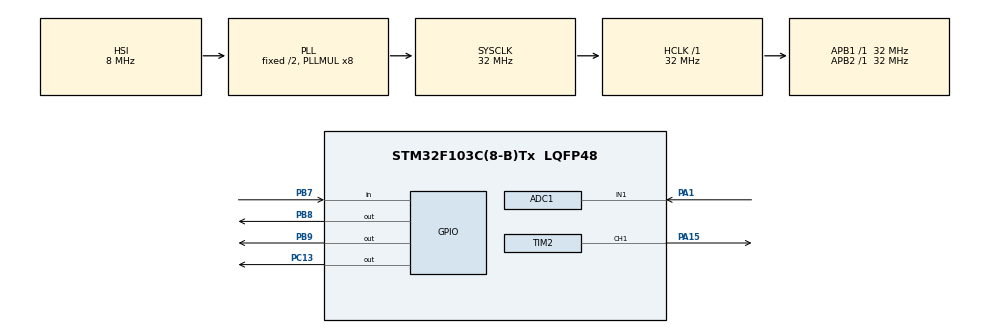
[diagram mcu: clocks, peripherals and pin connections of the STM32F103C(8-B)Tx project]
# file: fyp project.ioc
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ADC1.Channel-0\#ChannelRegularConversion=ADC_CHANNEL_1
ADC1.ContinuousConvMode=ENABLE
ADC1.NbrOfConversionFlag=1
ADC1.Rank-0\#ChannelRegularConversion=1
ADC1.SamplingTime-0\#ChannelRegularConversion=ADC_SAMPLETIME_1CYCLE_5
ADC1.master=1
Mcu.Family=STM32F1
Mcu.Name=STM32F103C(8-B)Tx
Mcu.Package=LQFP48
NVIC.PriorityGroup=NVIC_PRIORITYGROUP_4
PA1.Signal=ADCx_IN1
PA15.Signal=S_TIM2_CH1_ETR
PB7.Signal=GPIO_Input
PB8.Signal=GPIO_Output
PB9.Signal=GPIO_Output
PC13-TAMPER-RTC.Signal=GPIO_Output
PD0-OSC_IN.Mode=HSE-External-Oscillator
PD0-OSC_IN.Signal=RCC_OSC_IN
PD1-OSC_OUT.Mode=HSE-External-Oscillator
PD1-OSC_OUT.Signal=RCC_OSC_OUT
ProjectManager.HeapSize=0x200
ProjectManager.StackSize=0x400
ProjectManager.TargetToolchain=STM32CubeIDE
RCC.ADCPresc=RCC_ADCPCLK2_DIV4
RCC.AHBFreq_Value=32000000
RCC.APB1Freq_Value=32000000
RCC.APB1TimFreq_Value=32000000
RCC.APB2Freq_Value=32000000
RCC.APB2TimFreq_Value=32000000
RCC.HCLKFreq_Value=32000000
RCC.PLLMUL=RCC_PLL_MUL8
RCC.SYSCLKFreq_VALUE=32000000
RCC.SYSCLKSource=RCC_SYSCLKSOURCE_PLLCLK
RCC.USBFreq_Value=32000000
SH.ADCx_IN1.0=ADC1_IN1,IN1
SH.S_TIM2_CH1_ETR.0=TIM2_CH1,PWM Generation1 CH1
TIM1.Period=100
TIM1.Prescaler=2-1
TIM2.Channel-PWM\ Generation1\ CH1=TIM_CHANNEL_1
TIM2.Period=1000
TIM2.Prescaler=2-1
VP_SYS_VS_ND.Mode=No_Debug
VP_TIM1_VS_ClockSourceINT.Mode=Internal
VP_TIM2_VS_ClockSourceINT.Mode=Internal
board=custom

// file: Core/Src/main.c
/* USER CODE BEGIN Header */
/**
  ******************************************************************************
  * @file           : main.c
  * @brief          : Main program body
  ******************************************************************************
  * @attention
  *
  * Copyright (c) 2023 STMicroelectronics.
  * All rights reserved.
  *
  * This software is licensed under terms that can be found in the LICENSE file
  * in the root directory of this software component.
  * If no LICENSE file comes with this software, it is provided AS-IS.
  *
  ******************************************************************************
  */
/* USER CODE END Header */
#include "main.h"

/* USER CODE BEGIN Includes */
#include "lcd.h"
/* USER CODE END Includes */

ADC_HandleTypeDef hadc1;

TIM_HandleTypeDef htim1;
TIM_HandleTypeDef htim2;

/* USER CODE BEGIN PV */
uint16_t readValue1;
uint16_t readValue2;
uint16_t readValue3;
uint16_t readValue4;
uint16_t readValue5;
uint16_t readValue6;

uint16_t max_freq;
uint16_t curr_freq;
uint16_t min_freq;

uint16_t max_dc;
uint16_t curr_dc;
uint16_t min_dc;

uint16_t dis_freq;
uint16_t dis_dc;

int x=0,z=0;
int pre,xx=0,yy=0,jj=0;

ADC_ChannelConfTypeDef sConfigPrivate = {0};
/* USER CODE END PV */

void SystemClock_Config(void);
static void MX_GPIO_Init(void);
static void MX_ADC1_Init(void);
static void MX_TIM1_Init(void);
static void MX_TIM2_Init(void);

/* USER CODE BEGIN 0 */
void show()
{
	if(jj<2)
	{

	    lcd_put_cur(0,0);
	    displaySensorValueOnLCD(max_freq);

	     lcd_put_cur(0,5);

	     displaySensorValueOnLCD(curr_freq);

	     lcd_put_cur(0,10);
	     displaySensorValueOnLCD(min_freq);

	     lcd_put_cur(1,0);
	     displaySensorValueOnLCD(max_dc);

	    lcd_put_cur(1,5);
	    displaySensorValueOnLCD(curr_dc);

	     lcd_put_cur(1,10);
	     displaySensorValueOnLCD(min_dc);
	     jj=jj+1;

	}
	else
	{
	 lcd_clear();
	 jj=0;
	}

}
void show1() {
    if (jj < 2) {
        if (min_dc > max_dc) {
            lcd_clear();
            lcd_send_string(" ERROR   ");
        }
        if (min_freq > max_freq) {
            lcd_clear();
            lcd_send_string(" ERROR   ");
        }
        if (max_freq > min_freq && max_dc > min_dc) {
            if (curr_freq > max_freq) {
                dis_freq = max_freq;
            } else if (curr_freq < min_freq) {
                dis_freq = min_freq;
            } else if (curr_freq > min_freq && curr_freq < max_freq) {
                dis_freq = curr_freq;
            }
            if (curr_dc > max_dc) {
                dis_dc = max_dc;
            } else if (curr_dc < min_dc) {
                dis_dc = min_dc;
            } else if (curr_dc > min_dc && curr_dc < max_dc) {
                dis_dc = curr_dc;
            }

            lcd_put_cur(0, 0);
            displaySensorValueOnLCD(max_freq);
            lcd_put_cur(0, 5);
            displaySensorValueOnLCD(dis_freq);
            lcd_put_cur(0, 10);
            displaySensorValueOnLCD(min_freq);
            lcd_put_cur(1, 0);
            displaySensorValueOnLCD(max_dc);
            lcd_put_cur(1, 5);
            displaySensorValueOnLCD(dis_dc);
            lcd_put_cur(1, 10);
            displaySensorValueOnLCD(min_dc);

            float pre = 320000 / dis_freq;
            __HAL_TIM_SET_PRESCALER(&htim1, pre);
            TIM1->CCR1 = dis_dc;
            TIM1->CCR2 = dis_dc;
            jj = jj + 1;
        }
    } else {
        lcd_clear();
        jj = 0;
    }
}

void adc ()
{
	          sConfigPrivate.Rank = ADC_REGULAR_RANK_1;
		  	  sConfigPrivate.SamplingTime = ADC_SAMPLETIME_1CYCLE_5;
		  	  sConfigPrivate.Channel = ADC_CHANNEL_9;
		      HAL_ADC_ConfigChannel(&hadc1, &sConfigPrivate);
		  	  HAL_ADC_Start(&hadc1);
		  	  HAL_ADC_PollForConversion(&hadc1,1000);
		  	  readValue1 = HAL_ADC_GetValue(&hadc1);
		 	 if(readValue1> 3850)
		 	  			   	  {
		 	  			   		readValue1  =3850;
		 	  			   	  }

		  	  HAL_ADC_Stop(&hadc1);
		  	  sConfigPrivate.Channel = ADC_CHANNEL_0;
		  	  HAL_ADC_ConfigChannel(&hadc1, &sConfigPrivate);
		  	  HAL_ADC_Start(&hadc1);
		  	  HAL_ADC_PollForConversion(&hadc1,1000);
		  	  readValue2 = HAL_ADC_GetValue(&hadc1);
		  	 if(readValue2> 3850)
		  			   	  {
		  			   		readValue2  =3850;
		  			   	  }
		  	  HAL_ADC_Stop(&hadc1);
		  	  sConfigPrivate.Channel = ADC_CHANNEL_2;
		  	  HAL_ADC_ConfigChannel(&hadc1, &sConfigPrivate);
		  	  HAL_ADC_Start(&hadc1);
		  	  HAL_ADC_PollForConversion(&hadc1,1000);
		  	  readValue3 = HAL_ADC_GetValue(&hadc1);
		  	 if(readValue3> 3850)
		  			   	  {
		  			   		readValue3  =3850;
		  			   	  }
		  	  HAL_ADC_Stop(&hadc1);
		  	  sConfigPrivate.Channel = ADC_CHANNEL_6;
		      HAL_ADC_ConfigChannel(&hadc1, &sConfigPrivate);
	     	  HAL_ADC_Start(&hadc1);
	     	  HAL_ADC_PollForConversion(&hadc1,1000);
		   	  readValue4 = HAL_ADC_GetValue(&hadc1);
		   	 if(readValue4> 3850)
		   			   	  {
		   			   		readValue4  =3850;
		   			   	  }
		   	  HAL_ADC_Stop(&hadc1);
		   	  sConfigPrivate.Channel = ADC_CHANNEL_5;
		  	  HAL_ADC_ConfigChannel(&hadc1, &sConfigPrivate);
		   	  HAL_ADC_Start(&hadc1);
		   	  HAL_ADC_PollForConversion(&hadc1,1000);
		   	  readValue5 = HAL_ADC_GetValue(&hadc1);
		   	 if(readValue5> 3850)
		   			   	  {
		   			   		readValue5  =3850;
		   			   	  }
		   	  HAL_ADC_Stop(&hadc1);
			  sConfigPrivate.Channel = ADC_CHANNEL_4;
		   	  HAL_ADC_ConfigChannel(&hadc1, &sConfigPrivate);
		      HAL_ADC_Start(&hadc1);
		   	  HAL_ADC_PollForConversion(&hadc1,1000);
		   	  readValue6 = HAL_ADC_GetValue(&hadc1);
		   	 if(readValue6> 3850)
		   			   	  {
		   			   		readValue6  =3850;
		   			   	  }
		   	  HAL_ADC_Stop(&hadc1);

			  max_freq=(readValue1/3.85)*5;
			  curr_freq=(readValue2/3.85)*5;
			  min_freq=(readValue3/3.85)*5;
			  max_dc=(readValue4/38.5);
			  curr_dc=(readValue5/38.5);
			  min_dc=(readValue6/38.5);

}
void adc1 ()
{
	          sConfigPrivate.Rank = ADC_REGULAR_RANK_1;
		  	  sConfigPrivate.SamplingTime = ADC_SAMPLETIME_1CYCLE_5;

		  	  sConfigPrivate.Channel = ADC_CHANNEL_0;
		  	  HAL_ADC_ConfigChannel(&hadc1, &sConfigPrivate);
		  	  HAL_ADC_Start(&hadc1);
		  	  HAL_ADC_PollForConversion(&hadc1,1000);
		  	  readValue2 = HAL_ADC_GetValue(&hadc1);
		  	 if(readValue2> 3850)
		  			   	  {
		  			   		readValue2  =3850;
		  			   	  }
		  	  HAL_ADC_Stop(&hadc1);

		   	  sConfigPrivate.Channel = ADC_CHANNEL_5;
		  	  HAL_ADC_ConfigChannel(&hadc1, &sConfigPrivate);
		   	  HAL_ADC_Start(&hadc1);
		   	  HAL_ADC_PollForConversion(&hadc1,1000);
		   	  readValue5 = HAL_ADC_GetValue(&hadc1);
		   	 if(readValue5> 3850)
		   			   	  {
		   			   		readValue5  =3850;
		   			   	  }
		   	  HAL_ADC_Stop(&hadc1);

	  curr_freq=(readValue2/3.85)*5;

	  curr_dc=(readValue5/38.5);

}
/* USER CODE END 0 */

int main(void)
{

  /* MCU Configuration--------------------------------------------------------*/

  /* Reset of all peripherals, Initializes the Flash interface and the Systick. */
  HAL_Init();

  /* Configure the system clock */
  SystemClock_Config();

  /* Initialize all configured peripherals */
  MX_GPIO_Init();
  MX_ADC1_Init();
  MX_TIM1_Init();
  MX_TIM2_Init();
  /* USER CODE BEGIN 2 */
  lcd_init();

  HAL_TIM_PWM_Start(&htim1, TIM_CHANNEL_1);
  HAL_TIMEx_PWMN_Start(&htim1,TIM_CHANNEL_1);
  HAL_TIM_PWM_Start(&htim1, TIM_CHANNEL_2);
  HAL_TIMEx_PWMN_Start(&htim1,TIM_CHANNEL_2);
  /* USER CODE END 2 */

  /* Infinite loop */
  /* USER CODE BEGIN WHILE */
  while (1)
	  while (1) {
	      // HAL_GPIO_WritePin(GPIOC, GPIO_PIN_13, 1);
	      // HAL_GPIO_WritePin(GPIOC, GPIO_PIN_13, 0);

	      x = HAL_GPIO_ReadPin(GPIOB, GPIO_PIN_7);

	      if (x == 0) {
	          z++;
	          HAL_Delay(700);
	      }

	      if (z == 0) {
	          if (xx == 0) {
	              lcd_clear();
	              lcd_send_string("SETUP MODE");
	              lcd_clear();
	              xx = 1;
	              yy = 0;
	          }

	          HAL_GPIO_WritePin(GPIOC, GPIO_PIN_13, 1);
	          adc();
	          show();
	      }

	      if (z == 1) {
	          if (yy == 0) {
	              lcd_clear();
	              lcd_send_string("OUTPUT MODE");
	              lcd_clear();
	              xx = 0;
	              yy = 1;
	          }

	          HAL_GPIO_WritePin(GPIOC, GPIO_PIN_13, 0);
	          adc1();
	          show1();
	      }

	      if (z == 2) {
	          z = 0;
	      }

	      /* USER CODE END WHILE */

	  }
}

void SystemClock_Config(void)
{
  RCC_OscInitTypeDef RCC_OscInitStruct = {0};
  RCC_ClkInitTypeDef RCC_ClkInitStruct = {0};
  RCC_PeriphCLKInitTypeDef PeriphClkInit = {0};

  /** Initializes the RCC Oscillators according to the specified parameters
  * in the RCC_OscInitTypeDef structure.
  */
  RCC_OscInitStruct.OscillatorType = RCC_OSCILLATORTYPE_HSI;
  RCC_OscInitStruct.HSIState = RCC_HSI_ON;
  RCC_OscInitStruct.HSICalibrationValue = RCC_HSICALIBRATION_DEFAULT;
  RCC_OscInitStruct.PLL.PLLState = RCC_PLL_ON;
  RCC_OscInitStruct.PLL.PLLSource = RCC_PLLSOURCE_HSI_DIV2;
  RCC_OscInitStruct.PLL.PLLMUL = RCC_PLL_MUL8;
  if (HAL_RCC_OscConfig(&RCC_OscInitStruct) != HAL_OK)
  {
    Error_Handler();
  }

  /** Initializes the CPU, AHB and APB buses clocks
  */
  RCC_ClkInitStruct.ClockType = RCC_CLOCKTYPE_HCLK|RCC_CLOCKTYPE_SYSCLK
                              |RCC_CLOCKTYPE_PCLK1|RCC_CLOCKTYPE_PCLK2;
  RCC_ClkInitStruct.SYSCLKSource = RCC_SYSCLKSOURCE_PLLCLK;
  RCC_ClkInitStruct.AHBCLKDivider = RCC_SYSCLK_DIV1;
  RCC_ClkInitStruct.APB1CLKDivider = RCC_HCLK_DIV1;
  RCC_ClkInitStruct.APB2CLKDivider = RCC_HCLK_DIV1;

  if (HAL_RCC_ClockConfig(&RCC_ClkInitStruct, FLASH_LATENCY_1) != HAL_OK)
  {
    Error_Handler();
  }
  PeriphClkInit.PeriphClockSelection = RCC_PERIPHCLK_ADC;
  PeriphClkInit.AdcClockSelection = RCC_ADCPCLK2_DIV4;
  if (HAL_RCCEx_PeriphCLKConfig(&PeriphClkInit) != HAL_OK)
  {
    Error_Handler();
  }
}

static void MX_ADC1_Init(void)
{

  ADC_ChannelConfTypeDef sConfig = {0};

  /** Common config
  */
  hadc1.Instance = ADC1;
  hadc1.Init.ScanConvMode = ADC_SCAN_DISABLE;
  hadc1.Init.ContinuousConvMode = ENABLE;
  hadc1.Init.DiscontinuousConvMode = DISABLE;
  hadc1.Init.ExternalTrigConv = ADC_SOFTWARE_START;
  hadc1.Init.DataAlign = ADC_DATAALIGN_RIGHT;
  hadc1.Init.NbrOfConversion = 1;
  if (HAL_ADC_Init(&hadc1) != HAL_OK)
  {
    Error_Handler();
  }

  /** Configure Regular Channel
  */
  sConfig.Channel = ADC_CHANNEL_9;
  sConfig.Rank = ADC_REGULAR_RANK_1;
  sConfig.SamplingTime = ADC_SAMPLETIME_1CYCLE_5;
  if (HAL_ADC_ConfigChannel(&hadc1, &sConfig) != HAL_OK)
  {
    Error_Handler();
  }

}

static void MX_TIM1_Init(void)
{

  TIM_ClockConfigTypeDef sClockSourceConfig = {0};
  TIM_MasterConfigTypeDef sMasterConfig = {0};
  TIM_OC_InitTypeDef sConfigOC = {0};
  TIM_BreakDeadTimeConfigTypeDef sBreakDeadTimeConfig = {0};

  htim1.Instance = TIM1;
  htim1.Init.Prescaler = 2-1;
  htim1.Init.CounterMode = TIM_COUNTERMODE_UP;
  htim1.Init.Period = 100;
  htim1.Init.ClockDivision = TIM_CLOCKDIVISION_DIV1;
  htim1.Init.RepetitionCounter = 0;
  htim1.Init.AutoReloadPreload = TIM_AUTORELOAD_PRELOAD_DISABLE;
  if (HAL_TIM_Base_Init(&htim1) != HAL_OK)
  {
    Error_Handler();
  }
  sClockSourceConfig.ClockSource = TIM_CLOCKSOURCE_INTERNAL;
  if (HAL_TIM_ConfigClockSource(&htim1, &sClockSourceConfig) != HAL_OK)
  {
    Error_Handler();
  }
  if (HAL_TIM_PWM_Init(&htim1) != HAL_OK)
  {
    Error_Handler();
  }
  sMasterConfig.MasterOutputTrigger = TIM_TRGO_RESET;
  sMasterConfig.MasterSlaveMode = TIM_MASTERSLAVEMODE_DISABLE;
  if (HAL_TIMEx_MasterConfigSynchronization(&htim1, &sMasterConfig) != HAL_OK)
  {
    Error_Handler();
  }
  sConfigOC.OCMode = TIM_OCMODE_PWM1;
  sConfigOC.Pulse = 0;
  sConfigOC.OCPolarity = TIM_OCPOLARITY_HIGH;
  sConfigOC.OCNPolarity = TIM_OCNPOLARITY_HIGH;
  sConfigOC.OCFastMode = TIM_OCFAST_DISABLE;
  sConfigOC.OCIdleState = TIM_OCIDLESTATE_RESET;
  sConfigOC.OCNIdleState = TIM_OCNIDLESTATE_RESET;
  if (HAL_TIM_PWM_ConfigChannel(&htim1, &sConfigOC, TIM_CHANNEL_1) != HAL_OK)
  {
    Error_Handler();
  }
  if (HAL_TIM_PWM_ConfigChannel(&htim1, &sConfigOC, TIM_CHANNEL_2) != HAL_OK)
  {
    Error_Handler();
  }
  sBreakDeadTimeConfig.OffStateRunMode = TIM_OSSR_DISABLE;
  sBreakDeadTimeConfig.OffStateIDLEMode = TIM_OSSI_DISABLE;
  sBreakDeadTimeConfig.LockLevel = TIM_LOCKLEVEL_OFF;
  sBreakDeadTimeConfig.DeadTime = 6.4;
  sBreakDeadTimeConfig.BreakState = TIM_BREAK_DISABLE;
  sBreakDeadTimeConfig.BreakPolarity = TIM_BREAKPOLARITY_HIGH;
  sBreakDeadTimeConfig.AutomaticOutput = TIM_AUTOMATICOUTPUT_DISABLE;
  if (HAL_TIMEx_ConfigBreakDeadTime(&htim1, &sBreakDeadTimeConfig) != HAL_OK)
  {
    Error_Handler();
  }
  HAL_TIM_MspPostInit(&htim1);

}

static void MX_TIM2_Init(void)
{

  TIM_ClockConfigTypeDef sClockSourceConfig = {0};
  TIM_MasterConfigTypeDef sMasterConfig = {0};
  TIM_OC_InitTypeDef sConfigOC = {0};

  htim2.Instance = TIM2;
  htim2.Init.Prescaler = 2-1;
  htim2.Init.CounterMode = TIM_COUNTERMODE_UP;
  htim2.Init.Period = 1000;
  htim2.Init.ClockDivision = TIM_CLOCKDIVISION_DIV1;
  htim2.Init.AutoReloadPreload = TIM_AUTORELOAD_PRELOAD_DISABLE;
  if (HAL_TIM_Base_Init(&htim2) != HAL_OK)
  {
    Error_Handler();
  }
  sClockSourceConfig.ClockSource = TIM_CLOCKSOURCE_INTERNAL;
  if (HAL_TIM_ConfigClockSource(&htim2, &sClockSourceConfig) != HAL_OK)
  {
    Error_Handler();
  }
  if (HAL_TIM_PWM_Init(&htim2) != HAL_OK)
  {
    Error_Handler();
  }
  sMasterConfig.MasterOutputTrigger = TIM_TRGO_RESET;
  sMasterConfig.MasterSlaveMode = TIM_MASTERSLAVEMODE_DISABLE;
  if (HAL_TIMEx_MasterConfigSynchronization(&htim2, &sMasterConfig) != HAL_OK)
  {
    Error_Handler();
  }
  sConfigOC.OCMode = TIM_OCMODE_PWM1;
  sConfigOC.Pulse = 0;
  sConfigOC.OCPolarity = TIM_OCPOLARITY_HIGH;
  sConfigOC.OCFastMode = TIM_OCFAST_DISABLE;
  if (HAL_TIM_PWM_ConfigChannel(&htim2, &sConfigOC, TIM_CHANNEL_1) != HAL_OK)
  {
    Error_Handler();
  }
  HAL_TIM_MspPostInit(&htim2);

}

static void MX_GPIO_Init(void)
{
  GPIO_InitTypeDef GPIO_InitStruct = {0};

  /* GPIO Ports Clock Enable */
  __HAL_RCC_GPIOC_CLK_ENABLE();
  __HAL_RCC_GPIOD_CLK_ENABLE();
  __HAL_RCC_GPIOA_CLK_ENABLE();
  __HAL_RCC_GPIOB_CLK_ENABLE();

  /*Configure GPIO pin Output Level */
  HAL_GPIO_WritePin(GPIOC, GPIO_PIN_13, GPIO_PIN_RESET);

  /*Configure GPIO pin Output Level */
  HAL_GPIO_WritePin(GPIOB, GPIO_PIN_12|GPIO_PIN_13|GPIO_PIN_14|GPIO_PIN_15
                          |GPIO_PIN_8|GPIO_PIN_9, GPIO_PIN_RESET);

  /*Configure GPIO pin : PC13 */
  GPIO_InitStruct.Pin = GPIO_PIN_13;
  GPIO_InitStruct.Mode = GPIO_MODE_OUTPUT_PP;
  GPIO_InitStruct.Pull = GPIO_NOPULL;
  GPIO_InitStruct.Speed = GPIO_SPEED_FREQ_LOW;
  HAL_GPIO_Init(GPIOC, &GPIO_InitStruct);

  /*Configure GPIO pins : PB12 PB13 PB14 PB15
                           PB8 PB9 */
  GPIO_InitStruct.Pin = GPIO_PIN_12|GPIO_PIN_13|GPIO_PIN_14|GPIO_PIN_15
                          |GPIO_PIN_8|GPIO_PIN_9;
  GPIO_InitStruct.Mode = GPIO_MODE_OUTPUT_PP;
  GPIO_InitStruct.Pull = GPIO_NOPULL;
  GPIO_InitStruct.Speed = GPIO_SPEED_FREQ_LOW;
  HAL_GPIO_Init(GPIOB, &GPIO_InitStruct);

  /*Configure GPIO pin : PB7 */
  GPIO_InitStruct.Pin = GPIO_PIN_7;
  GPIO_InitStruct.Mode = GPIO_MODE_INPUT;
  GPIO_InitStruct.Pull = GPIO_PULLUP;
  HAL_GPIO_Init(GPIOB, &GPIO_InitStruct);

}

void Error_Handler(void)
{
  __disable_irq();
  while (1)
  {
  }
}
